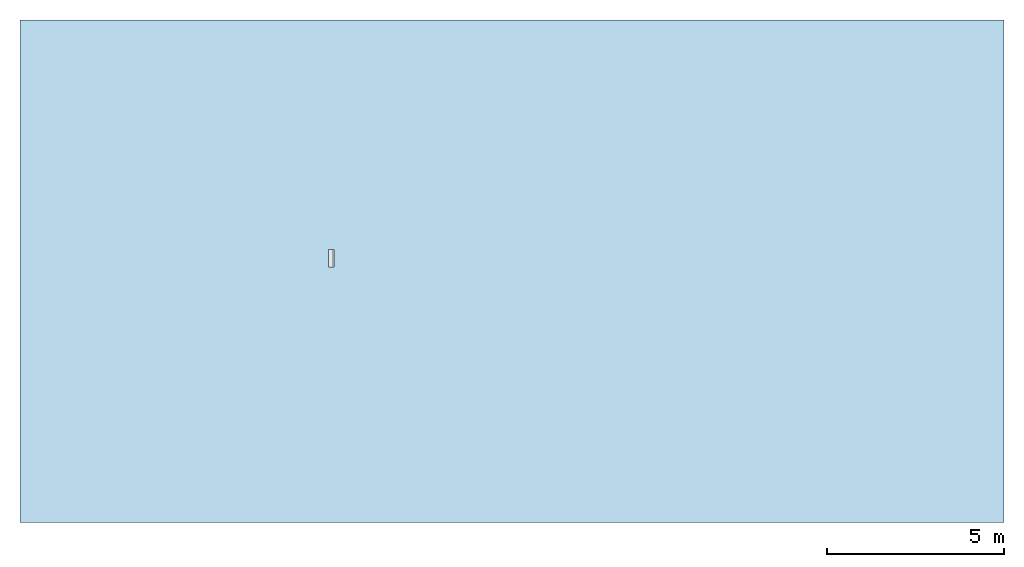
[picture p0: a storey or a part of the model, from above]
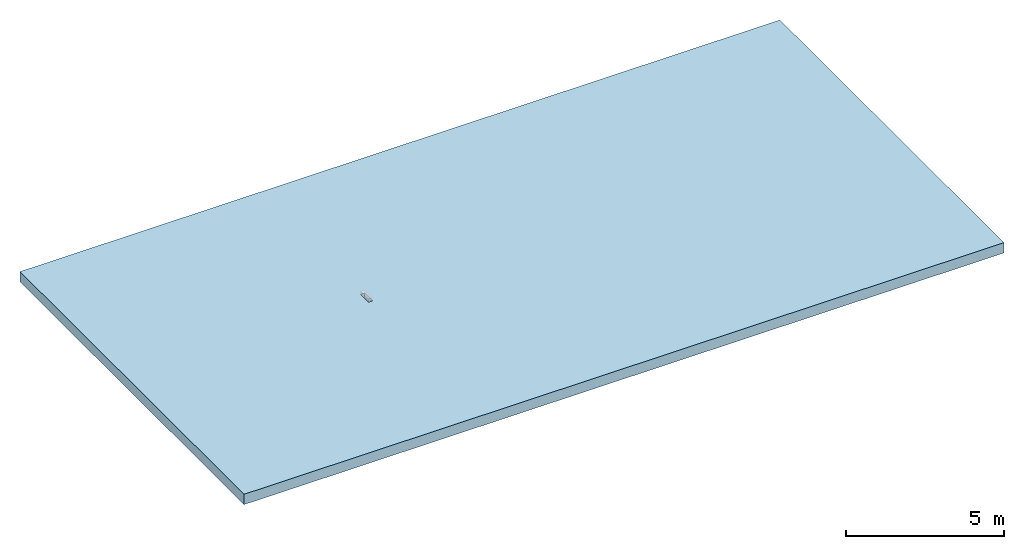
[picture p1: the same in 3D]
Properties of the parts of a building model (IFC2X3)

# File
Description: ViewDefinition [CoordinationView]
File name: 7962 - Access unit - 500mm LG.ifc
Time: 2013-09-18T15:28:09
Written by: Autodesk Revit 2013
Made in: 20120221_2030(x64)

# IfcProject, Project Number
LongName: Project Name; Phase: Project Status

# IfcSite, Default
RefLatitude: 42, 21, 30, 344238; RefLongitude: -71, -3, -35, -194702; RefElevation: 0 mm

# IfcBuilding
Pset_BuildingCommon - NumberOfStoreys: 1
Other - Project Issue Date: Issue Date; Client Name: Owner; Project Name: Project Name; Project Status: Project Status; Project Number: Project Number; Project Address: ## Street City, State Zip

# IfcBuildingStorey, Level 1
LongName: Level 1; Elevation: 0 mm
Constraints - Elevation Base: 0; Elevation: 0 mm
Graphics - Line Weight: 1; Symbol at End 2 Default: yes; Line Pattern: Center; Color: 0; Symbol at End 1 Default: no; Symbol: M_Level Head - Circle: M_Level Head - Circle
Identity Data - Name: Level 1; Structural: no; Building Story: yes
Dimensions - Computation Height: 0 mm

# IfcBuildingElementProxy: 7962 - Access unit - 500mm LG, Civil-Drainage-Channel-ACO-KerbDrain-HB305-File 1 of 2-Main Units:7962 - Access unit - 500mm LG:7962 - Access unit - 500mm LG:1188972
In: Level 1
Material: ACO Polymer Concrete., Iron, Cast
Phasing - Phase Created: New Construction
Dimensions - Volume: 13106563 mm3; Void_Length: 500 mm; I/O Endcap Void depth: 6000 mm; Staright Void Depth: -180 mm; Void_Width: 150 mm
Constraints - Level: Level: Level 1; Moves With Nearby Elements: no
Pset_BuildingElementProxyCommon - Reference: 7962 - Access unit - 500mm LG
Identity Data - Assembly Code: D2040; Installation guidelines: http://www.aco.co.uk/download.php?id=120; E-mail Sales: customersupport@aco.co.uk; Fax: +44 (0)1462 815895; Model: ACO KerbDrain HB305; URL: www.aco.co.uk; Model Description: Combined kerb and drainage system; Product brochure: http://www.aco.co.uk/download.php?id=120; Cost: 0; Manufacturer: ACO Technologies plc - ACO Water Management Division; Type Comments: ACO KerbDrain HB305 half battered access unit 500mm long; Price: POA - contact ACO; Maintenance guidelines: http://www.aco.co.uk/download.php?id=120; Assembly Description: Rain Water Drainage; Telephone: +44 (0)1462 816666; E-mail Technical: technical@aco.co.uk; OmniClass Number: 23.70.50.24; Product Page URL: http://www.aco.co.uk/product_detail.php?id=3; OmniClass Title: Rainwater Removal; Address: ACO Business Park, Hitchin Road, Shefford, Bedfordshire, United Kingdom SG17 5TE; Product Code: 7962
Materials and Finishes - Access Cover/Frame Finish: Water Based Paint Coating; End Cap Material: N/A; Channel Material: Vienite® Synthetic Resin Concrete; Access Cover/Frame Material: Ductile Iron; Connection Pipe Material Colour: N/A; End Cap Colour: N/A; Connection Pipe Material: N/A; Channel Colour: Grey; Access Cover/Frame Colour: Black
Construction - KDHB305 - LH drop kerb: no; I/O Pipe: no; KDHB305 - RH Inlet/outlet end cap: no; KDHB305 - RH drop kerb: no; KDHB305 - Access Unit: yes; KDHB305 - Channel unit - 500mm: no; KDHB305 - Closing end cap: no; KDHB305 - Channel unit - 1000mm: no; KDHB305 - Drainable centre stone: no; KDHB305 - Blind unit: no; KDHB305 - Perforated centre stone: no; KDHB305 - Channel unit - 250mm: no; KDHB305 - LH Inlet/Outlet end cap: no; KDHB305 - Flush RH dropkerb: no; KDHB305 - Centre stone: no; KDHB305 - Flush LH dropkerb: no
General - TagNumber: 0.000000; SerialNumber: 0.000000
Data - ACO Hydraulic Design Software: http://www.acodesign.co.uk; Hydraulic Performance: http://www.aco.co.uk/download.php?id=120; Invert Depth: 280mm; Product Standard: BS EN 1433:2002, CE marked, Kitemarked; Channel C.S.A: 0.02m²; Product Dimensions: 500mm x 150mm x 305mm (LxWxH); Drainage Slot Width: N/A; Product Weight: 28.7 Kg; Concrete Surround Volume - Load Class A 15 - D 400 - Concrete Pavement: 0.14m³/m; Connection Pipe O.D: N/A; Concrete Surround Volume - Load Class A 15 - D 400 - Grass or Asphalt Pavement: 0.13m³/m; Drainage Slot Intake area: N/A; Load Class: A 15 - D 400; Installation - Concrete Grade: Refer to brochure
Green Building Properties - End Cap Recycled Material Content: N/A; Access Cover/Frame Recycled Material Content: Between 40% - 90%; End Cap Recyclable: N/A; Channel Recycled Material Content: 20% minimum; Channel Recyclable: Fully recyclable; Access Cover/Frame Recyclable: Fully recyclable Fully recyclable
Other - Revision: 1; CreatedBy: www.aco.co.uk

# IfcOpeningElement: Recess (2)
In: Level 1
Constraints - Level: Level: Level 1; Height Offset From Level: 0 mm; Related to Mass: no; Room Bounding: yes
Dimensions - Area: 394760000 mm2; Perimeter: 84000 mm; Thickness: 400 mm; Volume: 157890500000 mm3
Phasing - Phase Created: New Construction
Structural - Enable Analytical Model: no; Structural: no
Analytical Properties - Roughness: 1; Absorptance: 0.1
Materials and Finishes - Structural Material: Plant
Construction - Function: 0; Default Thickness: 400 mm
Graphics - Coarse Scale Fill Color: 0

# IfcSlab: Floor:Generic Floor - 400mm, Floor:Generic Floor - 400mm:193825
In: Level 1
PredefinedType: FLOOR; Material: Plant 400 mm
Constraints - Level: Level: Level 1; Height Offset From Level: 0 mm; Related to Mass: no; Room Bounding: yes
Dimensions - Area: 394760000 mm2; Perimeter: 84000 mm; Thickness: 400 mm; Volume: 157890500000 mm3
Phasing - Phase Created: New Construction
Structural - Enable Analytical Model: no; Structural: no
Pset_SlabCommon - Reference: Generic Floor - 400mm; IsExternal: no; LoadBearing: yes
Analytical Properties - Roughness: 1; Absorptance: 0.1
Materials and Finishes - Structural Material: Plant
Construction - Function: 0; Default Thickness: 400 mm
Graphics - Coarse Scale Fill Color: 0
